VERSION 5.4 ;
NAMESCASESENSITIVE ON ;

UNITS
    DATABASE MICRONS 100 ;
END UNITS

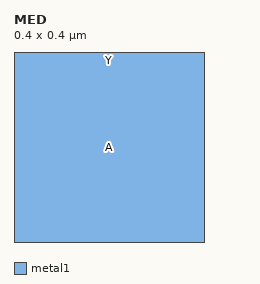
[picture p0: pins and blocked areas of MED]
MACRO MED
    CLASS CORE ;
    ORIGIN 0.000 0.000 ;
    SIZE 0.4 BY 0.4 ;
    SYMMETRY x y ;
    PIN Y
        DIRECTION OUTPUT ;
        PORT
        LAYER metal1 ;
        RECT 0.0 0.0 0.4 0.4 ;
        END
    END Y
    PIN A
        DIRECTION INPUT ;
        PORT
        LAYER metal1 ;
        RECT 0.0 0.0 0.4 0.4 ;
        END
    END A
END MED

END LIBRARY
